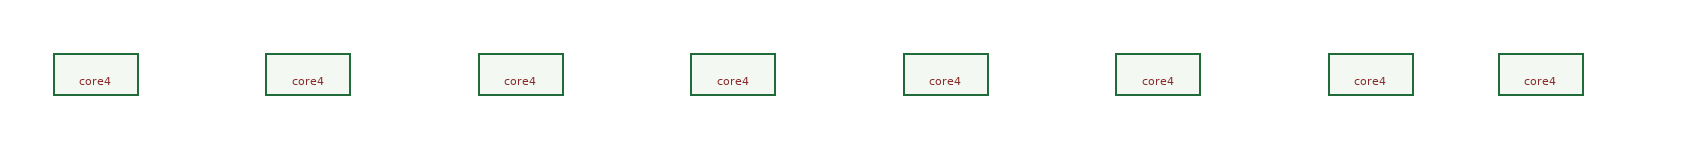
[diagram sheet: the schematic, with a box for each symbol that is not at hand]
v {xschem version=3.0.0 file_version=1.2 }
G {}
K {type=subcircuit
format="@name @pinlist @symname"
template="name=x1"
}
V {}
S {type=subcircuit
format="@name @pinlist @symname"
template="name=x1"
}
E {}
C {top/core4.sym} -680 0 0 0 {}
C {top/core4.sym} -480 0 0 0 {}
C {top/core4.sym} -280 0 0 0 {}
C {top/core4.sym} -80 0 0 0 {}
C {top/core4.sym} 120 0 0 0 {}
C {top/core4.sym} 320 0 0 0 {}
C {top/core4.sym} 520 0 0 0 {}
C {top/core4.sym} 680 0 0 0 {}
